VERSION 5.7 ;
  NOWIREEXTENSIONATPIN ON ;
  DIVIDERCHAR "/" ;
  BUSBITCHARS "[]" ;
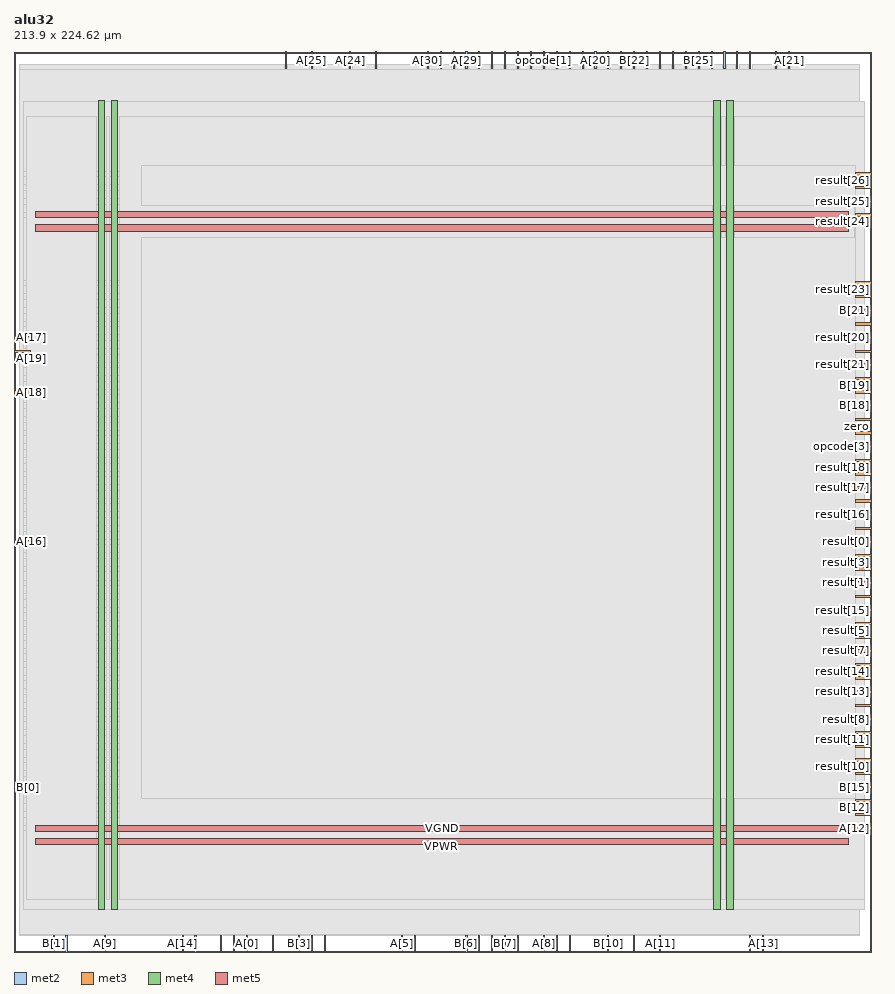
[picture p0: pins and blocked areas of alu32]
MACRO alu32
  CLASS BLOCK ;
  FOREIGN alu32 ;
  ORIGIN 0.000 0.000 ;
  SIZE 213.900 BY 224.620 ;
  PIN A[0]
    DIRECTION INPUT ;
    USE SIGNAL ;
    ANTENNAGATEAREA 0.196500 ;
    PORT
      LAYER met2 ;
        RECT 58.050 0.000 58.330 4.000 ;
    END
  END A[0]
  PIN A[10]
    DIRECTION INPUT ;
    USE SIGNAL ;
    ANTENNAGATEAREA 0.159000 ;
    PORT
      LAYER met2 ;
        RECT 45.170 0.000 45.450 4.000 ;
    END
  END A[10]
  PIN A[11]
    DIRECTION INPUT ;
    USE SIGNAL ;
    ANTENNAGATEAREA 0.196500 ;
    PORT
      LAYER met2 ;
        RECT 161.090 0.000 161.370 4.000 ;
    END
  END A[11]
  PIN A[12]
    DIRECTION INPUT ;
    USE SIGNAL ;
    ANTENNAGATEAREA 0.159000 ;
    PORT
      LAYER met3 ;
        RECT 209.900 30.640 213.900 31.240 ;
    END
  END A[12]
  PIN A[13]
    DIRECTION INPUT ;
    USE SIGNAL ;
    ANTENNAGATEAREA 0.126000 ;
    PORT
      LAYER met2 ;
        RECT 186.850 0.000 187.130 4.000 ;
    END
  END A[13]
  PIN A[14]
    DIRECTION INPUT ;
    USE SIGNAL ;
    ANTENNAGATEAREA 0.159000 ;
    PORT
      LAYER met2 ;
        RECT 41.950 0.000 42.230 4.000 ;
    END
  END A[14]
  PIN A[15]
    DIRECTION INPUT ;
    USE SIGNAL ;
    ANTENNAGATEAREA 0.196500 ;
    PORT
      LAYER met2 ;
        RECT 125.670 0.000 125.950 4.000 ;
    END
  END A[15]
  PIN A[16]
    DIRECTION INPUT ;
    USE SIGNAL ;
    ANTENNAGATEAREA 0.213000 ;
    PORT
      LAYER met3 ;
        RECT 0.000 102.040 4.000 102.640 ;
    END
  END A[16]
  PIN A[17]
    DIRECTION INPUT ;
    USE SIGNAL ;
    ANTENNAGATEAREA 0.213000 ;
    PORT
      LAYER met3 ;
        RECT 0.000 153.040 4.000 153.640 ;
    END
  END A[17]
  PIN A[18]
    DIRECTION INPUT ;
    USE SIGNAL ;
    ANTENNAGATEAREA 0.213000 ;
    PORT
      LAYER met3 ;
        RECT 0.000 139.440 4.000 140.040 ;
    END
  END A[18]
  PIN A[19]
    DIRECTION INPUT ;
    USE SIGNAL ;
    ANTENNAGATEAREA 0.213000 ;
    PORT
      LAYER met3 ;
        RECT 0.000 149.640 4.000 150.240 ;
    END
  END A[19]
  PIN A[1]
    DIRECTION INPUT ;
    USE SIGNAL ;
    ANTENNAGATEAREA 0.196500 ;
    PORT
      LAYER met2 ;
        RECT 64.490 0.000 64.770 4.000 ;
    END
  END A[1]
  PIN A[20]
    DIRECTION INPUT ;
    USE SIGNAL ;
    ANTENNAGATEAREA 0.213000 ;
    PORT
      LAYER met2 ;
        RECT 144.990 220.620 145.270 224.620 ;
    END
  END A[20]
  PIN A[21]
    DIRECTION INPUT ;
    USE SIGNAL ;
    ANTENNAGATEAREA 0.213000 ;
    PORT
      LAYER met2 ;
        RECT 193.290 220.620 193.570 224.620 ;
    END
  END A[21]
  PIN A[22]
    DIRECTION INPUT ;
    USE SIGNAL ;
    ANTENNAGATEAREA 0.196500 ;
    PORT
      LAYER met2 ;
        RECT 151.430 220.620 151.710 224.620 ;
    END
  END A[22]
  PIN A[23]
    DIRECTION INPUT ;
    USE SIGNAL ;
    ANTENNAGATEAREA 0.213000 ;
    PORT
      LAYER met2 ;
        RECT 109.570 220.620 109.850 224.620 ;
    END
  END A[23]
  PIN A[24]
    DIRECTION INPUT ;
    USE SIGNAL ;
    ANTENNAGATEAREA 0.159000 ;
    PORT
      LAYER met2 ;
        RECT 83.810 220.620 84.090 224.620 ;
    END
  END A[24]
  PIN A[25]
    DIRECTION INPUT ;
    USE SIGNAL ;
    ANTENNAGATEAREA 0.159000 ;
    PORT
      LAYER met2 ;
        RECT 74.150 220.620 74.430 224.620 ;
    END
  END A[25]
  PIN A[26]
    DIRECTION INPUT ;
    USE SIGNAL ;
    ANTENNAGATEAREA 0.213000 ;
    PORT
      LAYER met2 ;
        RECT 90.250 220.620 90.530 224.620 ;
    END
  END A[26]
  PIN A[27]
    DIRECTION INPUT ;
    USE SIGNAL ;
    ANTENNAGATEAREA 0.196500 ;
    PORT
      LAYER met2 ;
        RECT 67.710 220.620 67.990 224.620 ;
    END
  END A[27]
  PIN A[28]
    DIRECTION INPUT ;
    USE SIGNAL ;
    ANTENNAGATEAREA 0.159000 ;
    PORT
      LAYER met2 ;
        RECT 106.350 220.620 106.630 224.620 ;
    END
  END A[28]
  PIN A[29]
    DIRECTION INPUT ;
    USE SIGNAL ;
    ANTENNAGATEAREA 0.159000 ;
    PORT
      LAYER met2 ;
        RECT 112.790 220.620 113.070 224.620 ;
    END
  END A[29]
  PIN A[2]
    DIRECTION INPUT ;
    USE SIGNAL ;
    ANTENNAGATEAREA 0.196500 ;
    PORT
      LAYER met2 ;
        RECT 74.150 0.000 74.430 4.000 ;
    END
  END A[2]
  PIN A[30]
    DIRECTION INPUT ;
    USE SIGNAL ;
    ANTENNAGATEAREA 0.159000 ;
    PORT
      LAYER met2 ;
        RECT 103.130 220.620 103.410 224.620 ;
    END
  END A[30]
  PIN A[31]
    DIRECTION INPUT ;
    USE SIGNAL ;
    ANTENNAGATEAREA 0.196500 ;
    PORT
      LAYER met2 ;
        RECT 135.330 220.620 135.610 224.620 ;
    END
  END A[31]
  PIN A[3]
    DIRECTION INPUT ;
    USE SIGNAL ;
    ANTENNAGATEAREA 0.213000 ;
    PORT
      LAYER met2 ;
        RECT 54.830 0.000 55.110 4.000 ;
    END
  END A[3]
  PIN A[4]
    DIRECTION INPUT ;
    USE SIGNAL ;
    ANTENNAGATEAREA 0.126000 ;
    PORT
      LAYER met2 ;
        RECT 51.610 0.000 51.890 4.000 ;
    END
  END A[4]
  PIN A[5]
    DIRECTION INPUT ;
    USE SIGNAL ;
    ANTENNAGATEAREA 0.196500 ;
    PORT
      LAYER met2 ;
        RECT 96.690 0.000 96.970 4.000 ;
    END
  END A[5]
  PIN A[6]
    DIRECTION INPUT ;
    USE SIGNAL ;
    ANTENNAGATEAREA 0.196500 ;
    PORT
      LAYER met2 ;
        RECT 116.010 0.000 116.290 4.000 ;
    END
  END A[6]
  PIN A[7]
    DIRECTION INPUT ;
    USE SIGNAL ;
    ANTENNAGATEAREA 0.126000 ;
    PORT
      LAYER met2 ;
        RECT 119.230 0.000 119.510 4.000 ;
    END
  END A[7]
  PIN A[8]
    DIRECTION INPUT ;
    USE SIGNAL ;
    ANTENNAGATEAREA 0.196500 ;
    PORT
      LAYER met2 ;
        RECT 132.110 0.000 132.390 4.000 ;
    END
  END A[8]
  PIN A[9]
    DIRECTION INPUT ;
    USE SIGNAL ;
    ANTENNAGATEAREA 0.213000 ;
    PORT
      LAYER met2 ;
        RECT 22.630 0.000 22.910 4.000 ;
    END
  END A[9]
  PIN B[0]
    DIRECTION INPUT ;
    USE SIGNAL ;
    ANTENNAGATEAREA 0.196500 ;
    PORT
      LAYER met3 ;
        RECT 0.000 40.840 4.000 41.440 ;
    END
  END B[0]
  PIN B[10]
    DIRECTION INPUT ;
    USE SIGNAL ;
    ANTENNAGATEAREA 0.159000 ;
    PORT
      LAYER met2 ;
        RECT 148.210 0.000 148.490 4.000 ;
    END
  END B[10]
  PIN B[11]
    DIRECTION INPUT ;
    USE SIGNAL ;
    ANTENNAGATEAREA 0.159000 ;
    PORT
      LAYER met2 ;
        RECT 154.650 0.000 154.930 4.000 ;
    END
  END B[11]
  PIN B[12]
    DIRECTION INPUT ;
    USE SIGNAL ;
    ANTENNAGATEAREA 0.213000 ;
    PORT
      LAYER met3 ;
        RECT 209.900 34.040 213.900 34.640 ;
    END
  END B[12]
  PIN B[13]
    DIRECTION INPUT ;
    USE SIGNAL ;
    ANTENNAGATEAREA 0.196500 ;
    PORT
      LAYER met2 ;
        RECT 183.630 0.000 183.910 4.000 ;
    END
  END B[13]
  PIN B[14]
    DIRECTION INPUT ;
    USE SIGNAL ;
    ANTENNAGATEAREA 0.196500 ;
    PORT
      LAYER met3 ;
        RECT 209.900 37.440 213.900 38.040 ;
    END
  END B[14]
  PIN B[15]
    DIRECTION INPUT ;
    USE SIGNAL ;
    ANTENNAGATEAREA 0.159000 ;
    PORT
      LAYER met3 ;
        RECT 209.900 40.840 213.900 41.440 ;
    END
  END B[15]
  PIN B[16]
    DIRECTION INPUT ;
    USE SIGNAL ;
    ANTENNAGATEAREA 0.159000 ;
    PORT
      LAYER met3 ;
        RECT 209.900 105.440 213.900 106.040 ;
    END
  END B[16]
  PIN B[17]
    DIRECTION INPUT ;
    USE SIGNAL ;
    ANTENNAGATEAREA 0.159000 ;
    PORT
      LAYER met3 ;
        RECT 209.900 112.240 213.900 112.840 ;
    END
  END B[17]
  PIN B[18]
    DIRECTION INPUT ;
    USE SIGNAL ;
    ANTENNAGATEAREA 0.159000 ;
    PORT
      LAYER met3 ;
        RECT 209.900 136.040 213.900 136.640 ;
    END
  END B[18]
  PIN B[19]
    DIRECTION INPUT ;
    USE SIGNAL ;
    ANTENNAGATEAREA 0.159000 ;
    PORT
      LAYER met3 ;
        RECT 209.900 139.440 213.900 140.040 ;
    END
  END B[19]
  PIN B[1]
    DIRECTION INPUT ;
    USE SIGNAL ;
    ANTENNAGATEAREA 0.213000 ;
    PORT
      LAYER met2 ;
        RECT 9.750 0.000 10.030 4.000 ;
    END
  END B[1]
  PIN B[20]
    DIRECTION INPUT ;
    USE SIGNAL ;
    ANTENNAGATEAREA 0.196500 ;
    PORT
      LAYER met3 ;
        RECT 209.900 149.640 213.900 150.240 ;
    END
  END B[20]
  PIN B[21]
    DIRECTION INPUT ;
    USE SIGNAL ;
    ANTENNAGATEAREA 0.196500 ;
    PORT
      LAYER met3 ;
        RECT 209.900 159.840 213.900 160.440 ;
    END
  END B[21]
  PIN B[22]
    DIRECTION INPUT ;
    USE SIGNAL ;
    ANTENNAGATEAREA 0.196500 ;
    PORT
      LAYER met2 ;
        RECT 154.650 220.620 154.930 224.620 ;
    END
  END B[22]
  PIN B[23]
    DIRECTION INPUT ;
    USE SIGNAL ;
    ANTENNAGATEAREA 0.196500 ;
    PORT
      LAYER met2 ;
        RECT 161.090 220.620 161.370 224.620 ;
    END
  END B[23]
  PIN B[24]
    DIRECTION INPUT ;
    USE SIGNAL ;
    ANTENNAGATEAREA 0.213000 ;
    PORT
      LAYER met2 ;
        RECT 157.870 220.620 158.150 224.620 ;
    END
  END B[24]
  PIN B[25]
    DIRECTION INPUT ;
    USE SIGNAL ;
    ANTENNAGATEAREA 0.159000 ;
    PORT
      LAYER met2 ;
        RECT 170.750 220.620 171.030 224.620 ;
    END
  END B[25]
  PIN B[26]
    DIRECTION INPUT ;
    USE SIGNAL ;
    ANTENNAGATEAREA 0.159000 ;
    PORT
      LAYER met2 ;
        RECT 116.010 220.620 116.290 224.620 ;
    END
  END B[26]
  PIN B[27]
    DIRECTION INPUT ;
    USE SIGNAL ;
    ANTENNAGATEAREA 0.213000 ;
    PORT
      LAYER met2 ;
        RECT 148.210 220.620 148.490 224.620 ;
    END
  END B[27]
  PIN B[28]
    DIRECTION INPUT ;
    USE SIGNAL ;
    ANTENNAGATEAREA 0.159000 ;
    PORT
      LAYER met2 ;
        RECT 141.770 220.620 142.050 224.620 ;
    END
  END B[28]
  PIN B[29]
    DIRECTION INPUT ;
    USE SIGNAL ;
    ANTENNAGATEAREA 0.213000 ;
    PORT
      LAYER met2 ;
        RECT 119.230 220.620 119.510 224.620 ;
    END
  END B[29]
  PIN B[2]
    DIRECTION INPUT ;
    USE SIGNAL ;
    ANTENNAGATEAREA 0.247500 ;
    PORT
      LAYER met2 ;
        RECT 12.970 0.000 13.250 4.000 ;
    END
  END B[2]
  PIN B[30]
    DIRECTION INPUT ;
    USE SIGNAL ;
    ANTENNAGATEAREA 0.196500 ;
    PORT
      LAYER met2 ;
        RECT 122.450 220.620 122.730 224.620 ;
    END
  END B[30]
  PIN B[31]
    DIRECTION INPUT ;
    USE SIGNAL ;
    ANTENNAGATEAREA 0.213000 ;
    PORT
      LAYER met2 ;
        RECT 138.550 220.620 138.830 224.620 ;
    END
  END B[31]
  PIN B[3]
    DIRECTION INPUT ;
    USE SIGNAL ;
    ANTENNAGATEAREA 0.213000 ;
    PORT
      LAYER met2 ;
        RECT 70.930 0.000 71.210 4.000 ;
    END
  END B[3]
  PIN B[4]
    DIRECTION INPUT ;
    USE SIGNAL ;
    ANTENNAGATEAREA 0.213000 ;
    PORT
      LAYER met2 ;
        RECT 77.370 0.000 77.650 4.000 ;
    END
  END B[4]
  PIN B[5]
    DIRECTION INPUT ;
    USE SIGNAL ;
    ANTENNAGATEAREA 0.213000 ;
    PORT
      LAYER met2 ;
        RECT 99.910 0.000 100.190 4.000 ;
    END
  END B[5]
  PIN B[6]
    DIRECTION INPUT ;
    USE SIGNAL ;
    ANTENNAGATEAREA 0.159000 ;
    PORT
      LAYER met2 ;
        RECT 112.790 0.000 113.070 4.000 ;
    END
  END B[6]
  PIN B[7]
    DIRECTION INPUT ;
    USE SIGNAL ;
    ANTENNAGATEAREA 0.159000 ;
    PORT
      LAYER met2 ;
        RECT 122.450 0.000 122.730 4.000 ;
    END
  END B[7]
  PIN B[8]
    DIRECTION INPUT ;
    USE SIGNAL ;
    ANTENNAGATEAREA 0.196500 ;
    PORT
      LAYER met2 ;
        RECT 135.330 0.000 135.610 4.000 ;
    END
  END B[8]
  PIN B[9]
    DIRECTION INPUT ;
    USE SIGNAL ;
    ANTENNAGATEAREA 0.159000 ;
    PORT
      LAYER met2 ;
        RECT 138.550 0.000 138.830 4.000 ;
    END
  END B[9]
  PIN VGND
    DIRECTION INOUT ;
    USE GROUND ;
    PORT
      LAYER met4 ;
        RECT 24.340 10.640 25.940 212.400 ;
    END
    PORT
      LAYER met4 ;
        RECT 177.940 10.640 179.540 212.400 ;
    END
    PORT
      LAYER met5 ;
        RECT 5.280 30.030 208.160 31.630 ;
    END
    PORT
      LAYER met5 ;
        RECT 5.280 183.210 208.160 184.810 ;
    END
  END VGND
  PIN VPWR
    DIRECTION INOUT ;
    USE POWER ;
    PORT
      LAYER met4 ;
        RECT 21.040 10.640 22.640 212.400 ;
    END
    PORT
      LAYER met4 ;
        RECT 174.640 10.640 176.240 212.400 ;
    END
    PORT
      LAYER met5 ;
        RECT 5.280 26.730 208.160 28.330 ;
    END
    PORT
      LAYER met5 ;
        RECT 5.280 179.910 208.160 181.510 ;
    END
  END VPWR
  PIN carry
    DIRECTION OUTPUT ;
    USE SIGNAL ;
    ANTENNADIFFAREA 0.795200 ;
    PORT
      LAYER met2 ;
        RECT 167.530 220.620 167.810 224.620 ;
    END
  END carry
  PIN clk
    DIRECTION INPUT ;
    USE SIGNAL ;
    ANTENNAGATEAREA 0.852000 ;
    PORT
      LAYER met3 ;
        RECT 209.900 166.640 213.900 167.240 ;
    END
  END clk
  PIN negative
    DIRECTION OUTPUT ;
    USE SIGNAL ;
    ANTENNADIFFAREA 0.795200 ;
    PORT
      LAYER met2 ;
        RECT 190.070 220.620 190.350 224.620 ;
    END
  END negative
  PIN opcode[0]
    DIRECTION INPUT ;
    USE SIGNAL ;
    ANTENNAGATEAREA 0.213000 ;
    PORT
      LAYER met2 ;
        RECT 128.890 220.620 129.170 224.620 ;
    END
  END opcode[0]
  PIN opcode[1]
    DIRECTION INPUT ;
    USE SIGNAL ;
    ANTENNAGATEAREA 0.159000 ;
    PORT
      LAYER met2 ;
        RECT 132.110 220.620 132.390 224.620 ;
    END
  END opcode[1]
  PIN opcode[2]
    DIRECTION INPUT ;
    USE SIGNAL ;
    ANTENNAGATEAREA 0.213000 ;
    PORT
      LAYER met3 ;
        RECT 209.900 132.640 213.900 133.240 ;
    END
  END opcode[2]
  PIN opcode[3]
    DIRECTION INPUT ;
    USE SIGNAL ;
    ANTENNAGATEAREA 0.159000 ;
    PORT
      LAYER met3 ;
        RECT 209.900 125.840 213.900 126.440 ;
    END
  END opcode[3]
  PIN opcode[4]
    DIRECTION INPUT ;
    USE SIGNAL ;
    ANTENNAGATEAREA 0.159000 ;
    PORT
      LAYER met2 ;
        RECT 125.670 220.620 125.950 224.620 ;
    END
  END opcode[4]
  PIN overflow
    DIRECTION OUTPUT ;
    USE SIGNAL ;
    ANTENNADIFFAREA 0.795200 ;
    PORT
      LAYER met2 ;
        RECT 164.310 220.620 164.590 224.620 ;
    END
  END overflow
  PIN result[0]
    DIRECTION OUTPUT ;
    USE SIGNAL ;
    ANTENNADIFFAREA 0.445500 ;
    PORT
      LAYER met3 ;
        RECT 209.900 102.040 213.900 102.640 ;
    END
  END result[0]
  PIN result[10]
    DIRECTION OUTPUT ;
    USE SIGNAL ;
    ANTENNADIFFAREA 0.445500 ;
    PORT
      LAYER met3 ;
        RECT 209.900 44.240 213.900 44.840 ;
    END
  END result[10]
  PIN result[11]
    DIRECTION OUTPUT ;
    USE SIGNAL ;
    ANTENNADIFFAREA 0.445500 ;
    PORT
      LAYER met3 ;
        RECT 209.900 54.440 213.900 55.040 ;
    END
  END result[11]
  PIN result[12]
    DIRECTION OUTPUT ;
    USE SIGNAL ;
    ANTENNADIFFAREA 0.445500 ;
    PORT
      LAYER met3 ;
        RECT 209.900 78.240 213.900 78.840 ;
    END
  END result[12]
  PIN result[13]
    DIRECTION OUTPUT ;
    USE SIGNAL ;
    ANTENNADIFFAREA 0.445500 ;
    PORT
      LAYER met3 ;
        RECT 209.900 64.640 213.900 65.240 ;
    END
  END result[13]
  PIN result[14]
    DIRECTION OUTPUT ;
    USE SIGNAL ;
    ANTENNADIFFAREA 0.445500 ;
    PORT
      LAYER met3 ;
        RECT 209.900 68.040 213.900 68.640 ;
    END
  END result[14]
  PIN result[15]
    DIRECTION OUTPUT ;
    USE SIGNAL ;
    ANTENNADIFFAREA 0.445500 ;
    PORT
      LAYER met3 ;
        RECT 209.900 85.040 213.900 85.640 ;
    END
  END result[15]
  PIN result[16]
    DIRECTION OUTPUT ;
    USE SIGNAL ;
    ANTENNADIFFAREA 0.445500 ;
    PORT
      LAYER met3 ;
        RECT 209.900 108.840 213.900 109.440 ;
    END
  END result[16]
  PIN result[17]
    DIRECTION OUTPUT ;
    USE SIGNAL ;
    ANTENNADIFFAREA 0.445500 ;
    PORT
      LAYER met3 ;
        RECT 209.900 115.640 213.900 116.240 ;
    END
  END result[17]
  PIN result[18]
    DIRECTION OUTPUT ;
    USE SIGNAL ;
    ANTENNADIFFAREA 0.445500 ;
    PORT
      LAYER met3 ;
        RECT 209.900 119.040 213.900 119.640 ;
    END
  END result[18]
  PIN result[19]
    DIRECTION OUTPUT ;
    USE SIGNAL ;
    ANTENNADIFFAREA 0.445500 ;
    PORT
      LAYER met3 ;
        RECT 209.900 122.440 213.900 123.040 ;
    END
  END result[19]
  PIN result[1]
    DIRECTION OUTPUT ;
    USE SIGNAL ;
    ANTENNADIFFAREA 0.445500 ;
    PORT
      LAYER met3 ;
        RECT 209.900 91.840 213.900 92.440 ;
    END
  END result[1]
  PIN result[20]
    DIRECTION OUTPUT ;
    USE SIGNAL ;
    ANTENNADIFFAREA 0.445500 ;
    PORT
      LAYER met3 ;
        RECT 209.900 153.040 213.900 153.640 ;
    END
  END result[20]
  PIN result[21]
    DIRECTION OUTPUT ;
    USE SIGNAL ;
    ANTENNADIFFAREA 0.445500 ;
    PORT
      LAYER met3 ;
        RECT 209.900 146.240 213.900 146.840 ;
    END
  END result[21]
  PIN result[22]
    DIRECTION OUTPUT ;
    USE SIGNAL ;
    ANTENNADIFFAREA 0.445500 ;
    PORT
      LAYER met3 ;
        RECT 209.900 156.440 213.900 157.040 ;
    END
  END result[22]
  PIN result[23]
    DIRECTION OUTPUT ;
    USE SIGNAL ;
    ANTENNADIFFAREA 0.445500 ;
    PORT
      LAYER met3 ;
        RECT 209.900 163.240 213.900 163.840 ;
    END
  END result[23]
  PIN result[24]
    DIRECTION OUTPUT ;
    USE SIGNAL ;
    ANTENNADIFFAREA 0.445500 ;
    PORT
      LAYER met3 ;
        RECT 209.900 183.640 213.900 184.240 ;
    END
  END result[24]
  PIN result[25]
    DIRECTION OUTPUT ;
    USE SIGNAL ;
    ANTENNADIFFAREA 0.445500 ;
    PORT
      LAYER met3 ;
        RECT 209.900 187.040 213.900 187.640 ;
    END
  END result[25]
  PIN result[26]
    DIRECTION OUTPUT ;
    USE SIGNAL ;
    ANTENNADIFFAREA 0.445500 ;
    PORT
      LAYER met3 ;
        RECT 209.900 190.440 213.900 191.040 ;
    END
  END result[26]
  PIN result[27]
    DIRECTION OUTPUT ;
    USE SIGNAL ;
    ANTENNADIFFAREA 0.445500 ;
    PORT
      LAYER met3 ;
        RECT 209.900 193.840 213.900 194.440 ;
    END
  END result[27]
  PIN result[28]
    DIRECTION OUTPUT ;
    USE SIGNAL ;
    ANTENNADIFFAREA 0.795200 ;
    PORT
      LAYER met2 ;
        RECT 173.970 220.620 174.250 224.620 ;
    END
  END result[28]
  PIN result[29]
    DIRECTION OUTPUT ;
    USE SIGNAL ;
    ANTENNADIFFAREA 0.795200 ;
    PORT
      LAYER met2 ;
        RECT 180.410 220.620 180.690 224.620 ;
    END
  END result[29]
  PIN result[2]
    DIRECTION OUTPUT ;
    USE SIGNAL ;
    ANTENNADIFFAREA 0.445500 ;
    PORT
      LAYER met3 ;
        RECT 209.900 95.240 213.900 95.840 ;
    END
  END result[2]
  PIN result[30]
    DIRECTION OUTPUT ;
    USE SIGNAL ;
    ANTENNADIFFAREA 0.795200 ;
    PORT
      LAYER met2 ;
        RECT 177.190 220.620 177.470 224.620 ;
    END
  END result[30]
  PIN result[31]
    DIRECTION OUTPUT ;
    USE SIGNAL ;
    ANTENNADIFFAREA 0.795200 ;
    PORT
      LAYER met2 ;
        RECT 183.630 220.620 183.910 224.620 ;
    END
  END result[31]
  PIN result[3]
    DIRECTION OUTPUT ;
    USE SIGNAL ;
    ANTENNADIFFAREA 0.445500 ;
    PORT
      LAYER met3 ;
        RECT 209.900 98.640 213.900 99.240 ;
    END
  END result[3]
  PIN result[4]
    DIRECTION OUTPUT ;
    USE SIGNAL ;
    ANTENNADIFFAREA 0.445500 ;
    PORT
      LAYER met3 ;
        RECT 209.900 88.440 213.900 89.040 ;
    END
  END result[4]
  PIN result[5]
    DIRECTION OUTPUT ;
    USE SIGNAL ;
    ANTENNADIFFAREA 0.445500 ;
    PORT
      LAYER met3 ;
        RECT 209.900 81.640 213.900 82.240 ;
    END
  END result[5]
  PIN result[6]
    DIRECTION OUTPUT ;
    USE SIGNAL ;
    ANTENNADIFFAREA 0.445500 ;
    PORT
      LAYER met3 ;
        RECT 209.900 71.440 213.900 72.040 ;
    END
  END result[6]
  PIN result[7]
    DIRECTION OUTPUT ;
    USE SIGNAL ;
    ANTENNADIFFAREA 0.445500 ;
    PORT
      LAYER met3 ;
        RECT 209.900 74.840 213.900 75.440 ;
    END
  END result[7]
  PIN result[8]
    DIRECTION OUTPUT ;
    USE SIGNAL ;
    ANTENNADIFFAREA 0.445500 ;
    PORT
      LAYER met3 ;
        RECT 209.900 57.840 213.900 58.440 ;
    END
  END result[8]
  PIN result[9]
    DIRECTION OUTPUT ;
    USE SIGNAL ;
    ANTENNADIFFAREA 0.445500 ;
    PORT
      LAYER met3 ;
        RECT 209.900 61.240 213.900 61.840 ;
    END
  END result[9]
  PIN rst_n
    DIRECTION INPUT ;
    USE SIGNAL ;
    ANTENNAGATEAREA 0.196500 ;
    PORT
      LAYER met3 ;
        RECT 209.900 142.840 213.900 143.440 ;
    END
  END rst_n
  PIN valid_in
    DIRECTION INPUT ;
    USE SIGNAL ;
    ANTENNAGATEAREA 0.196500 ;
    PORT
      LAYER met3 ;
        RECT 209.900 47.640 213.900 48.240 ;
    END
  END valid_in
  PIN valid_out
    DIRECTION OUTPUT ;
    USE SIGNAL ;
    ANTENNADIFFAREA 0.445500 ;
    PORT
      LAYER met3 ;
        RECT 209.900 51.040 213.900 51.640 ;
    END
  END valid_out
  PIN zero
    DIRECTION OUTPUT ;
    USE SIGNAL ;
    ANTENNADIFFAREA 0.445500 ;
    PORT
      LAYER met3 ;
        RECT 209.900 129.240 213.900 129.840 ;
    END
  END zero
  OBS
      LAYER nwell ;
        RECT 5.330 10.795 208.110 212.245 ;
      LAYER li1 ;
        RECT 5.520 10.795 207.920 212.245 ;
      LAYER met1 ;
        RECT 1.450 10.640 211.070 213.140 ;
      LAYER met2 ;
        RECT 1.480 220.340 67.430 221.410 ;
        RECT 68.270 220.340 73.870 221.410 ;
        RECT 74.710 220.340 83.530 221.410 ;
        RECT 84.370 220.340 89.970 221.410 ;
        RECT 90.810 220.340 102.850 221.410 ;
        RECT 103.690 220.340 106.070 221.410 ;
        RECT 106.910 220.340 109.290 221.410 ;
        RECT 110.130 220.340 112.510 221.410 ;
        RECT 113.350 220.340 115.730 221.410 ;
        RECT 116.570 220.340 118.950 221.410 ;
        RECT 119.790 220.340 122.170 221.410 ;
        RECT 123.010 220.340 125.390 221.410 ;
        RECT 126.230 220.340 128.610 221.410 ;
        RECT 129.450 220.340 131.830 221.410 ;
        RECT 132.670 220.340 135.050 221.410 ;
        RECT 135.890 220.340 138.270 221.410 ;
        RECT 139.110 220.340 141.490 221.410 ;
        RECT 142.330 220.340 144.710 221.410 ;
        RECT 145.550 220.340 147.930 221.410 ;
        RECT 148.770 220.340 151.150 221.410 ;
        RECT 151.990 220.340 154.370 221.410 ;
        RECT 155.210 220.340 157.590 221.410 ;
        RECT 158.430 220.340 160.810 221.410 ;
        RECT 161.650 220.340 164.030 221.410 ;
        RECT 164.870 220.340 167.250 221.410 ;
        RECT 168.090 220.340 170.470 221.410 ;
        RECT 171.310 220.340 173.690 221.410 ;
        RECT 174.530 220.340 176.910 221.410 ;
        RECT 177.750 220.340 180.130 221.410 ;
        RECT 180.970 220.340 183.350 221.410 ;
        RECT 184.190 220.340 189.790 221.410 ;
        RECT 190.630 220.340 193.010 221.410 ;
        RECT 193.850 220.340 211.050 221.410 ;
        RECT 1.480 4.280 211.050 220.340 ;
        RECT 1.480 4.000 9.470 4.280 ;
        RECT 10.310 4.000 12.690 4.280 ;
        RECT 13.530 4.000 22.350 4.280 ;
        RECT 23.190 4.000 41.670 4.280 ;
        RECT 42.510 4.000 44.890 4.280 ;
        RECT 45.730 4.000 51.330 4.280 ;
        RECT 52.170 4.000 54.550 4.280 ;
        RECT 55.390 4.000 57.770 4.280 ;
        RECT 58.610 4.000 64.210 4.280 ;
        RECT 65.050 4.000 70.650 4.280 ;
        RECT 71.490 4.000 73.870 4.280 ;
        RECT 74.710 4.000 77.090 4.280 ;
        RECT 77.930 4.000 96.410 4.280 ;
        RECT 97.250 4.000 99.630 4.280 ;
        RECT 100.470 4.000 112.510 4.280 ;
        RECT 113.350 4.000 115.730 4.280 ;
        RECT 116.570 4.000 118.950 4.280 ;
        RECT 119.790 4.000 122.170 4.280 ;
        RECT 123.010 4.000 125.390 4.280 ;
        RECT 126.230 4.000 131.830 4.280 ;
        RECT 132.670 4.000 135.050 4.280 ;
        RECT 135.890 4.000 138.270 4.280 ;
        RECT 139.110 4.000 147.930 4.280 ;
        RECT 148.770 4.000 154.370 4.280 ;
        RECT 155.210 4.000 160.810 4.280 ;
        RECT 161.650 4.000 183.350 4.280 ;
        RECT 184.190 4.000 186.570 4.280 ;
        RECT 187.410 4.000 211.050 4.280 ;
      LAYER met3 ;
        RECT 2.365 194.840 212.250 212.325 ;
        RECT 2.365 193.440 209.500 194.840 ;
        RECT 2.365 191.440 212.250 193.440 ;
        RECT 2.365 190.040 209.500 191.440 ;
        RECT 2.365 188.040 212.250 190.040 ;
        RECT 2.365 186.640 209.500 188.040 ;
        RECT 2.365 184.640 212.250 186.640 ;
        RECT 2.365 183.240 209.500 184.640 ;
        RECT 2.365 167.640 212.250 183.240 ;
        RECT 2.365 166.240 209.500 167.640 ;
        RECT 2.365 164.240 212.250 166.240 ;
        RECT 2.365 162.840 209.500 164.240 ;
        RECT 2.365 160.840 212.250 162.840 ;
        RECT 2.365 159.440 209.500 160.840 ;
        RECT 2.365 157.440 212.250 159.440 ;
        RECT 2.365 156.040 209.500 157.440 ;
        RECT 2.365 154.040 212.250 156.040 ;
        RECT 4.400 152.640 209.500 154.040 ;
        RECT 2.365 150.640 212.250 152.640 ;
        RECT 4.400 149.240 209.500 150.640 ;
        RECT 2.365 147.240 212.250 149.240 ;
        RECT 2.365 145.840 209.500 147.240 ;
        RECT 2.365 143.840 212.250 145.840 ;
        RECT 2.365 142.440 209.500 143.840 ;
        RECT 2.365 140.440 212.250 142.440 ;
        RECT 4.400 139.040 209.500 140.440 ;
        RECT 2.365 137.040 212.250 139.040 ;
        RECT 2.365 135.640 209.500 137.040 ;
        RECT 2.365 133.640 212.250 135.640 ;
        RECT 2.365 132.240 209.500 133.640 ;
        RECT 2.365 130.240 212.250 132.240 ;
        RECT 2.365 128.840 209.500 130.240 ;
        RECT 2.365 126.840 212.250 128.840 ;
        RECT 2.365 125.440 209.500 126.840 ;
        RECT 2.365 123.440 212.250 125.440 ;
        RECT 2.365 122.040 209.500 123.440 ;
        RECT 2.365 120.040 212.250 122.040 ;
        RECT 2.365 118.640 209.500 120.040 ;
        RECT 2.365 116.640 212.250 118.640 ;
        RECT 2.365 115.240 209.500 116.640 ;
        RECT 2.365 113.240 212.250 115.240 ;
        RECT 2.365 111.840 209.500 113.240 ;
        RECT 2.365 109.840 212.250 111.840 ;
        RECT 2.365 108.440 209.500 109.840 ;
        RECT 2.365 106.440 212.250 108.440 ;
        RECT 2.365 105.040 209.500 106.440 ;
        RECT 2.365 103.040 212.250 105.040 ;
        RECT 4.400 101.640 209.500 103.040 ;
        RECT 2.365 99.640 212.250 101.640 ;
        RECT 2.365 98.240 209.500 99.640 ;
        RECT 2.365 96.240 212.250 98.240 ;
        RECT 2.365 94.840 209.500 96.240 ;
        RECT 2.365 92.840 212.250 94.840 ;
        RECT 2.365 91.440 209.500 92.840 ;
        RECT 2.365 89.440 212.250 91.440 ;
        RECT 2.365 88.040 209.500 89.440 ;
        RECT 2.365 86.040 212.250 88.040 ;
        RECT 2.365 84.640 209.500 86.040 ;
        RECT 2.365 82.640 212.250 84.640 ;
        RECT 2.365 81.240 209.500 82.640 ;
        RECT 2.365 79.240 212.250 81.240 ;
        RECT 2.365 77.840 209.500 79.240 ;
        RECT 2.365 75.840 212.250 77.840 ;
        RECT 2.365 74.440 209.500 75.840 ;
        RECT 2.365 72.440 212.250 74.440 ;
        RECT 2.365 71.040 209.500 72.440 ;
        RECT 2.365 69.040 212.250 71.040 ;
        RECT 2.365 67.640 209.500 69.040 ;
        RECT 2.365 65.640 212.250 67.640 ;
        RECT 2.365 64.240 209.500 65.640 ;
        RECT 2.365 62.240 212.250 64.240 ;
        RECT 2.365 60.840 209.500 62.240 ;
        RECT 2.365 58.840 212.250 60.840 ;
        RECT 2.365 57.440 209.500 58.840 ;
        RECT 2.365 55.440 212.250 57.440 ;
        RECT 2.365 54.040 209.500 55.440 ;
        RECT 2.365 52.040 212.250 54.040 ;
        RECT 2.365 50.640 209.500 52.040 ;
        RECT 2.365 48.640 212.250 50.640 ;
        RECT 2.365 47.240 209.500 48.640 ;
        RECT 2.365 45.240 212.250 47.240 ;
        RECT 2.365 43.840 209.500 45.240 ;
        RECT 2.365 41.840 212.250 43.840 ;
        RECT 4.400 40.440 209.500 41.840 ;
        RECT 2.365 38.440 212.250 40.440 ;
        RECT 2.365 37.040 209.500 38.440 ;
        RECT 2.365 35.040 212.250 37.040 ;
        RECT 2.365 33.640 209.500 35.040 ;
        RECT 2.365 31.640 212.250 33.640 ;
        RECT 2.365 30.240 209.500 31.640 ;
        RECT 2.365 10.715 212.250 30.240 ;
      LAYER met4 ;
        RECT 3.055 13.095 20.640 208.585 ;
        RECT 23.040 13.095 23.940 208.585 ;
        RECT 26.340 13.095 174.240 208.585 ;
        RECT 176.640 13.095 177.540 208.585 ;
        RECT 179.940 13.095 212.225 208.585 ;
      LAYER met5 ;
        RECT 31.860 186.410 210.100 196.300 ;
        RECT 209.760 178.310 210.100 186.410 ;
        RECT 31.860 38.300 210.100 178.310 ;
  END
END alu32
END LIBRARY

